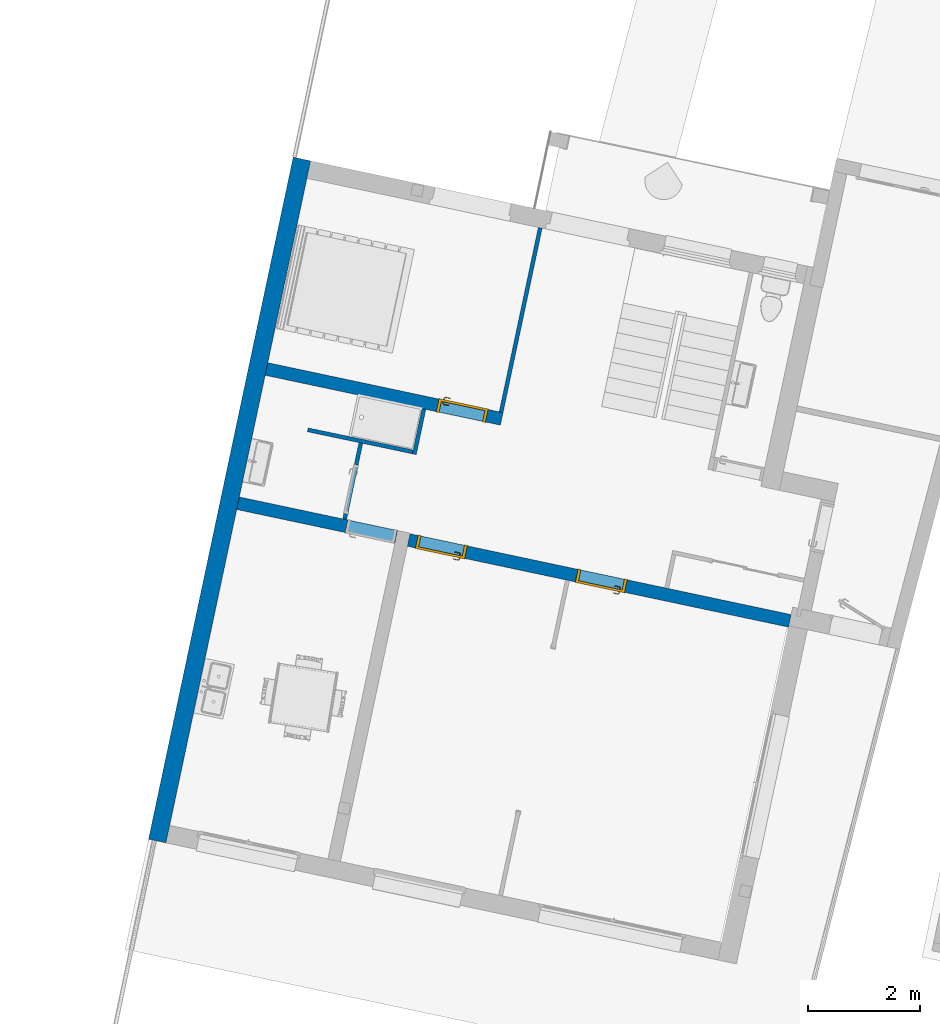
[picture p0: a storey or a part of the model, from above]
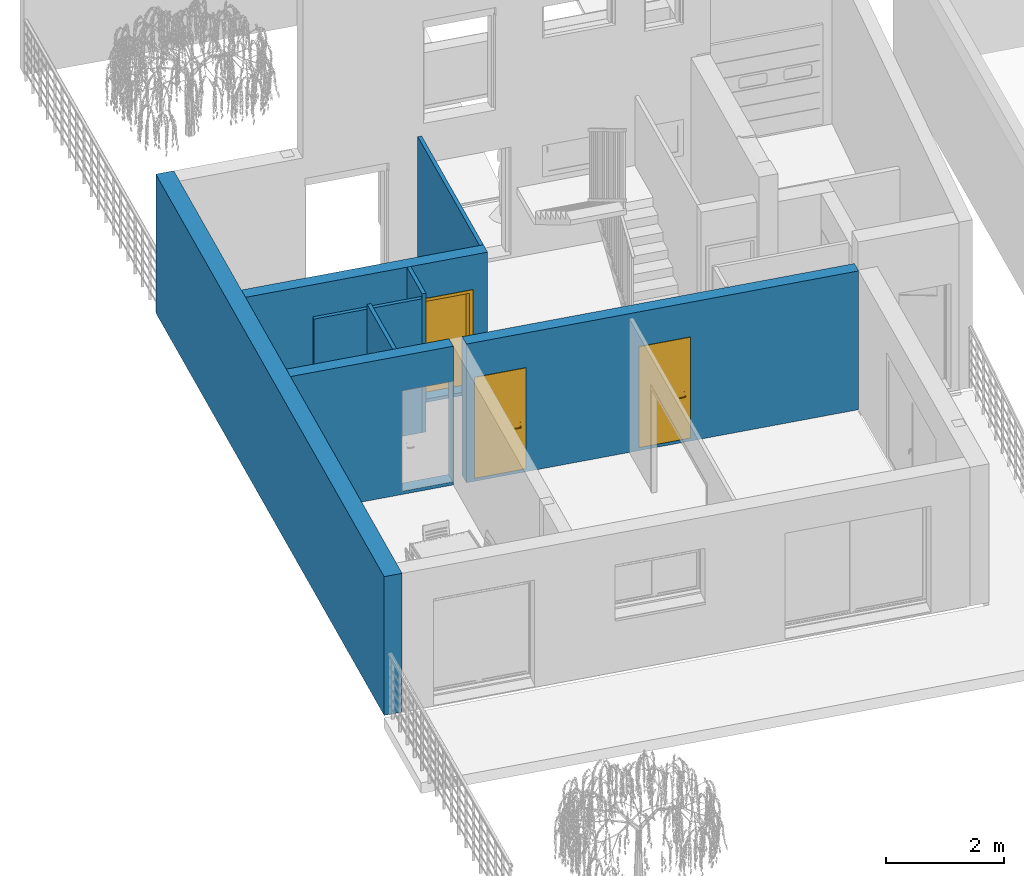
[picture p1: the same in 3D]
Properties of the parts of a building model (IFC2X3)

# File
Description: ViewDefinition [CoordinationView_V2.0]
Time: 2022-10-11T14:27:31
Written by: The EXPRESS Data Manager Version 5.02.0100.07 : 28 Aug 2013
Made in: 20190327_2315(x64) - Exporter 20.0.0.377 - Interface utilisateur alternative 20.0.0.377
Comment: STEP Physical File produced by: The EXPRESS Data Manager Version 5.02.0100.07 : 28 Aug 2013 * Module: EDMstepFileFactory/EDMstandAlone * Creation date: Tue Oct 11 14:27:31 2022 * Host: Khodri-Mohamed * Database: C:\Users\KHODRI~1\AppData\Local\Temp\b8559ccf-3b1b-4d22-95b2-55f6bca857a5\28f0a63c-8f12-43ca-b958-e8c956d41420\ifc * Database version: 5507 * Database creation date: Tue Oct 11 14:27:18 2022 * Schema: IFC2X3 * Model: DataRepository.ifc * Model creation date: Tue Oct 11 14:27:19 2022 * Header model: DataRepository.ifc_HeaderModel * Header model creation date: Tue Oct 11 14:27:19 2022 * EDMuser: sdai-user * EDMgroup: sdai-group * License ID and type: 5605 : Permanent license. Expiry date: * EDMstepFileFactory options: 020000

# IfcProject
LongName: CONSTRUCTION D'UNE HABITATION PRINCIPALE; Phase: PERMIS DE CONSTRUIRE

# IfcSite, Default
RefLatitude: 48, 52, 53, 759999; RefLongitude: 2, 25, 58, 79999; RefElevation: 0 m

# IfcSite: Portail PVC double - 01:Portail PVC double -3 m couleur noir ht 1,40 3, Portail PVC double - 01:Portail PVC double -3 m couleur noir ht 1,40 3:1927708
Material: Peinture - Noir, PVC - Gris fonçé

# IfcSite: Portail PVC simple - 01:Portail PVC simple -ht 1,40 m couleur gris, Portail PVC simple - 01:Portail PVC simple -ht 1,40 m couleur gris:1927764
Material: Peinture - Noir, PVC - Gris fonçé

# IfcBuilding
Pset_BuildingCommon - NumberOfStoreys: 4

# IfcBuildingStorey: Niveau:Ligne du Niveau (4)
Name | LongName | Elevation (m)
RDC | RDC | -0.0686872
Plan des fondations Maisons 1 et 2 | Plan des fondations Maisons 1 et 2 | 0
ETAGE | ETAGE | 2.8
Etage 1 | Etage 1 | 2.82

# IfcSpace (22)
InteriorOrExteriorSpace: INTERNAL
Name | In | LongName | Reference
626 | RDC | SALON 2 | SALON 2 626
627 | RDC | SALON 1 | SALON 1 627
628 | RDC | CUISINE | CUISINE 628
629 | RDC | SDB | SDB 629
630 | RDC | CH P | CH P 630
632 | RDC | GARAGE | GARAGE 632
633 | RDC | ENTREE | ENTREE 633
634 | RDC | PL | PL 634
637 | ETAGE | ch 4 | ch 4 637
638 | ETAGE | ch 2 | ch 2 638
639 | ETAGE | ch 1 | ch 1 639
641 | ETAGE | wc | wc 641
643 | RDC | WC | WC 643
644 | ETAGE | ch 3 | ch 3 644
645 | ETAGE | degt | degt 645
647 | ETAGE | sdb | sdb 647
648 | ETAGE | . | . 648
649 | ETAGE | . | . 649
656 | ETAGE | . | . 656
657 | ETAGE | . | . 657
658 | RDC | HALL | HALL 658
659 | RDC | Pièce | Pièce 659

# IfcBeam: 10 x 35 ht, Poutre rectangulaire - Béton:10 x 35 ht:1884701
In: Etage 1
Type - PredefinedType: BEAM
Type - Pset_BeamCommon - IsExternal: no; Reference: 10 x 35 ht
Type - Pset_QuantityTakeOff - Reference: 10 x 35 ht
Type - Pset_ReinforcementBarPitchOfBeam - Reference: 10 x 35 ht
Material: Béton - Béton coulé sur place; Group: Groupe de modèles:pergolas 2:1884699
Pset_BeamCommon - Span: 5.46 m; Slope: 0 deg
Pset_QuantityTakeOff - sets with these values: 2

# IfcBeam: 5 x 25 ht 2 (19)
In: Etage 1
Type - PredefinedType: BEAM
Type - Pset_BeamCommon - IsExternal: no; Reference: 5 x 25 ht 2
Type - Pset_QuantityTakeOff - Reference: 5 x 25 ht 2
Type - Pset_ReinforcementBarPitchOfBeam - Reference: 5 x 25 ht 2
Material: Béton - Béton coulé sur place; Group: Groupe de modèles:pergolas 2:1884699
Pset_BeamCommon - Slope: 0 deg
Pset_QuantityTakeOff - sets with these values: 2
Name (Poutre rectangulaire - Béton:5 x 25 ht 2:...) | Span (m)
1884707 | 1.66
1884709 | 1.66
1884711 | 1.646
1884713 | 1.631
1884715 | 1.616
1884717 | 1.601
1884719 | 1.587
1884721 | 1.572
1884723 | 1.557
1884725 | 1.542
1884727 | 1.528
1884729 | 1.513
1884731 | 1.498
1884733 | 1.484
1884737 | 1.468
1884739 | 1.453
1884741 | 1.438
1884743 | 1.424
1884745 | 1.409

# IfcBuildingElementProxy: LaRon, RPC Homme:LaRon:1914914
In: 657
Type - Pset_BuildingElementProxyCommon - Reference: LaRon
Type - Pset_QuantityTakeOff - Reference: LaRon
Pset_BuildingElementProxyCommon - sets with these values: 2

# IfcBuildingElementProxy: Lisa, RPC Femme:Lisa:1914892
In: 656
Type - Pset_BuildingElementProxyCommon - Reference: Lisa
Type - Pset_QuantityTakeOff - Reference: Lisa
Pset_BuildingElementProxyCommon - sets with these values: 2

# IfcBuildingElementProxy: Saule pleureur - 2.5 (4)
In: RDC
Type - Pset_BuildingElementProxyCommon - Reference: Saule pleureur - 2.5
Type - Pset_QuantityTakeOff - Reference: Saule pleureur - 2.5
Pset_BuildingElementProxyCommon - sets with these values: 2
Name (Arbre 3D - Saule pleureur:Saule pleureur - 2.5:...)
1939919
1939948
1939965
1939994

# IfcBuildingElementProxy: YinYin, RPC Femme:YinYin:1914956
In: RDC
Type - Pset_BuildingElementProxyCommon - Reference: YinYin
Type - Pset_QuantityTakeOff - Reference: YinYin
Pset_BuildingElementProxyCommon - sets with these values: 2

# IfcColumn: 20 X 20 (5)
Type - PredefinedType: COLUMN
Type - Pset_ColumnCommon - IsExternal: no; Reference: 20 X 20; LoadBearing: yes
Type - Pset_QuantityTakeOff - Reference: 20 X 20
Type - Pset_ReinforcementBarPitchOfColumn - Reference: 20 X 20
Pset_ColumnCommon - Slope: 0 deg
Pset_QuantityTakeOff - sets with these values: 2
Name (M_Béton-Carré-Poteau:20 X 20:...) | In | Material
1884703 | Plan des fondations Maisons 1 et 2 | Maçonnerie - Béton coulé sur place | Group: Groupe de modèles:pergolas 2:1884699
1884705 | Plan des fondations Maisons 1 et 2 | Maçonnerie - Béton coulé sur place | Group: Groupe de modèles:pergolas 2:1884699
1897064 | RDC | Béton - Béton coulé sur place
1897142 | RDC | Béton - Béton coulé sur place
1897328 | RDC | Béton - Béton coulé sur place

# IfcDoor: 140 - 90 x 210 cm - Gris, Avec panneau latéral:140 - 90 x 210 cm - Gris:1884574
In: Plan des fondations Maisons 1 et 2
Type - ParameterTakesPrecedence: no; Sizeable: no; Material: Peinture époxy - Gris, Verre
OverallHeight: 2.225 m; OverallWidth: 1.53 m
Pset_DoorCommon - IsExternal: yes; Reference: 140 - 90 x 210 cm - Gris
Pset_QuantityTakeOff - Reference: 140 - 90 x 210 cm - Gris

# IfcDoor: 83 x 204 - (80), FR_Simple (R):83 x 204 - (80):1891026
In: Plan des fondations Maisons 1 et 2
Type - OperationType: SINGLE_SWING_LEFT; ParameterTakesPrecedence: no; Sizeable: no; Material: Poignée Porte, Dormants Portes, Panneaux Portes
Type - FR_Simple (R):83 x 204 - (80):1891026 - PanelOperation: SWINGING
OverallHeight: 2.075 m; OverallWidth: 0.9 m
Pset_DoorCommon - IsExternal: no; Reference: 83 x 204 - (80)
Pset_QuantityTakeOff - Reference: 83 x 204 - (80)

# IfcDoor: 83 x 204 - (80), FR_Simple (R):83 x 204 - (80):1904554
In: Plan des fondations Maisons 1 et 2
Type - OperationType: SINGLE_SWING_LEFT; ParameterTakesPrecedence: no; Sizeable: no; Material: Poignée Porte, Dormants Portes, Panneaux Portes
Type - FR_Simple (R):83 x 204 - (80):1904554 - PanelOperation: SWINGING
OverallHeight: 2.075 m; OverallWidth: 0.9 m
Pset_DoorCommon - IsExternal: no; Reference: 83 x 204 - (80)
Pset_QuantityTakeOff - Reference: 83 x 204 - (80)

# IfcDoor: 83 x 204 - (80), FR_Simple (R):83 x 204 - (80):1884583
In: Plan des fondations Maisons 1 et 2
Type - OperationType: SINGLE_SWING_RIGHT; ParameterTakesPrecedence: no; Sizeable: no; Material: Poignée Porte, Dormants Portes, Panneaux Portes
Type - FR_Simple (R):83 x 204 - (80):1884583 - PanelOperation: SWINGING
OverallHeight: 2.075 m; OverallWidth: 0.9 m
Pset_DoorCommon - IsExternal: no; Reference: 83 x 204 - (80)
Pset_QuantityTakeOff - Reference: 83 x 204 - (80)

# IfcDoor: 83 x 204 - (80) (4)
In: Plan des fondations Maisons 1 et 2
Type - OperationType: SINGLE_SWING_RIGHT; ParameterTakesPrecedence: no; Sizeable: no; Material: Poignée Porte, Dormants Portes, Panneaux Portes
Type - FR_Simple (R):83 x 204 - (80):1884588 - PanelOperation: SWINGING
OverallHeight: 2.075 m; OverallWidth: 0.9 m
Pset_DoorCommon - IsExternal: no; Reference: 83 x 204 - (80)
Pset_QuantityTakeOff - Reference: 83 x 204 - (80)
Name (FR_Simple (R):83 x 204 - (80):...)
1884588
1884635
1884654
1891205

# IfcDoor: Garage sectionnelle 2.4 M x 2.00 ht, Garage sectionnelle:Garage sectionnelle 2.4 M x 2.00 ht:1884623
In: Plan des fondations Maisons 1 et 2
Type - ParameterTakesPrecedence: no; Sizeable: no; Material: Plastique - Noir, Peinture - Gris, Verre, Peinture - Grise
OverallHeight: 2.4 m; OverallWidth: 2.015 m
Pset_DoorCommon - IsExternal: no; Reference: Garage sectionnelle 2.4 M x 2.00 ht; ThermalTransmittance: 3.7021 kg/K/s3
Pset_QuantityTakeOff - Reference: Garage sectionnelle 2.4 M x 2.00 ht

# IfcDoor: Ouverture en rectangle 1.00 M, Ouverture en rectangle:Ouverture en rectangle 1.00 M:1884818
In: Plan des fondations Maisons 1 et 2
Type - ParameterTakesPrecedence: no; Sizeable: no; Material: RAL 212
OverallHeight: 2.35 m; OverallWidth: 1 m
Pset_DoorCommon - IsExternal: no; Reference: Ouverture en rectangle 1.00 M
Pset_QuantityTakeOff - Reference: Ouverture en rectangle 1.00 M

# IfcDoor: Ouverture en rectangle 3m, Ouverture en rectangle:Ouverture en rectangle 3m:1893428
In: RDC
Type - ParameterTakesPrecedence: no; Sizeable: no; Material: Bois - Chêne
OverallHeight: 2.15 m; OverallWidth: 3 m
Pset_DoorCommon - IsExternal: no; Reference: Ouverture en rectangle 3m
Pset_QuantityTakeOff - Reference: Ouverture en rectangle 3m

# IfcDoor: Ouverture en rectangle 4.50 M 3, Ouverture en rectangle:Ouverture en rectangle 4.50 M 3:1884817
In: RDC
Type - ParameterTakesPrecedence: no; Sizeable: no; Material: RAL 212
OverallHeight: 2.35 m; OverallWidth: 4.5 m
Pset_DoorCommon - IsExternal: no; Reference: Ouverture en rectangle 4.50 M 3
Pset_QuantityTakeOff - Reference: Ouverture en rectangle 4.50 M 3

# IfcDoor: PP (0.73m x 2.04m) (2)
In: ETAGE
Type - OperationType: SINGLE_SWING_LEFT; ParameterTakesPrecedence: no; Sizeable: no; Material: Finition Peinture - Blanc satiné, Bois - Mélaminé hêtre
Type - Int. Simple:PP (0.73m x 2.04m):1917461 - PanelOperation: SWINGING
OverallHeight: 2.075 m; OverallWidth: 0.8 m
Pset_DoorCommon - IsExternal: no; Reference: PP (0.73m x 2.04m); ThermalTransmittance: 3.7021 kg/K/s3
Pset_QuantityTakeOff - Reference: PP (0.73m x 2.04m)
Name (Int. Simple:PP (0.73m x 2.04m):...)
1917461
1930670

# IfcDoor: PP (0.73m x 2.04m) (2)
In: ETAGE
Type - OperationType: SINGLE_SWING_RIGHT; ParameterTakesPrecedence: no; Sizeable: no; Material: Finition Peinture - Blanc satiné, Bois - Mélaminé hêtre
Type - Int. Simple:PP (0.73m x 2.04m):1899424 - PanelOperation: SWINGING
OverallHeight: 2.075 m; OverallWidth: 0.8 m
Pset_DoorCommon - IsExternal: no; Reference: PP (0.73m x 2.04m); ThermalTransmittance: 3.7021 kg/K/s3
Pset_QuantityTakeOff - Reference: PP (0.73m x 2.04m)
Name (Int. Simple:PP (0.73m x 2.04m):...)
1899424
1930071

# IfcDoor: PP (0.73m x 2.04m) (2)
In: ETAGE
Type - OperationType: SINGLE_SWING_RIGHT; ParameterTakesPrecedence: no; Sizeable: no; Material: Finition Peinture - Blanc satiné, Bois - Mélaminé hêtre
Type - Int. Simple:PP (0.73m x 2.04m):1901654 - PanelOperation: SWINGING
OverallHeight: 2.075 m; OverallWidth: 0.8 m
Pset_DoorCommon - IsExternal: no; Reference: PP (0.73m x 2.04m); ThermalTransmittance: 3.7021 kg/K/s3
Pset_QuantityTakeOff - Reference: PP (0.73m x 2.04m)
Name (Int. Simple:PP (0.73m x 2.04m):...)
1901654
1912241

# IfcDoor: PP Oculus haut (0.90m x 2.15m), Ext. Simple:PP Oculus haut (0.90m x 2.15m):1884629
In: Plan des fondations Maisons 1 et 2
Type - OperationType: SINGLE_SWING_RIGHT; ParameterTakesPrecedence: no; Sizeable: no; Material: PVC - Blanc, Verre
Type - Ext. Simple:PP Oculus haut (0.90m x 2.15m):1884629 - PanelOperation: SWINGING
OverallHeight: 2.2 m; OverallWidth: 1 m
Pset_DoorCommon - IsExternal: yes; Reference: PP Oculus haut (0.90m x 2.15m)
Pset_QuantityTakeOff - Reference: PP Oculus haut (0.90m x 2.15m)

# IfcDoor: Placard coulissante - 2 panneaux, Placard coulissante - 2 panneaux:Placard coulissante - 2 panneaux:1894947
In: RDC
Type - ParameterTakesPrecedence: no; Sizeable: no; Material: Placard - Profil, Placard - Encadrement, Placard - Porte
OverallHeight: 2.1 m; OverallWidth: 1.2 m
Pset_DoorCommon - IsExternal: no; Reference: Placard coulissante - 2 panneaux
Pset_QuantityTakeOff - Reference: Placard coulissante - 2 panneaux

# IfcFlowTerminal: Baignoire rectangulaire - Mur:Baignoire rectangulaire - Mur 70 x 170, Baignoire rectangulaire - Mur:Baignoire rectangulaire - Mur 70 x 170:1929937
In: 647
Material: Céramique - Blanche
Pset_DistributionFlowElementCommon - Reference: Baignoire rectangulaire - Mur 70 x 170; sets with these values: 2

# IfcFlowTerminal: FR_Bac à douches - Vidange Axée:80 X 140, FR_Bac à douches - Vidange Axée:80 X 140:1912669
In: 645
Classification: D2010710 Showers (Uniformat); Material: Blanc - Element de salle de bains
Pset_DistributionFlowElementCommon - Reference: 80 X 140; sets with these values: 2

# IfcFlowTerminal: FR_Bac à douches - Vidange Axée:80 x 120 (5)
Classification: D2010710 Showers (Uniformat); Material: Blanc - Element de salle de bains
Pset_DistributionFlowElementCommon - Reference: 80 x 120; sets with these values: 2
Name (FR_Bac à douches - Vidange Axée:80 x 120:...) | In
1884580 | 629
1912712 | 645
1912743 | 645
1912770 | 649
1912811 | 639

# IfcFlowTerminal: Lavabo sur console métallique:100 x 47 x 85 cm - Blanc, Lavabo sur console métallique:100 x 47 x 85 cm - Blanc:1912585
In: 647
Material: Métal - Chrome, Céramique - Blanc
Pset_DistributionFlowElementCommon - Reference: 100 x 47 x 85 cm - Blanc; sets with these values: 2

# IfcFlowTerminal: Lavabo sur console métallique:80 x 40 x 85 cm - Blanc 3 (2)
Material: Métal - Chrome, Céramique - Blanc
Pset_DistributionFlowElementCommon - Reference: 80 x 40 x 85 cm - Blanc 3; sets with these values: 2
Name (Lavabo sur console métallique:80 x 40 x 85 cm - Blanc 3:...) | In
1884581 | 629
1884582 | 643

# IfcFlowTerminal: M_Cuvette réservoir-3D:M_Cuvette réservoir-3D (2)
Material: Porcelaine - Lin, Stratifié - Lin,Mat
Pset_DistributionFlowElementCommon - Reference: M_Cuvette réservoir-3D; sets with these values: 2
Name (M_Cuvette réservoir-3D:M_Cuvette réservoir-3D:...) | In
1884586 | 643
1912626 | 641

# IfcFlowTerminal: M_Evier-Double:1000 x 535 mm, M_Evier-Double:1000 x 535 mm:1884590
In: 628
Material: Métal - Acier, Poli
Pset_DistributionFlowElementCommon - Reference: 1000 x 535 mm; sets with these values: 2

# IfcFurnishingElement: 1,40 mm x 2000 mm 2 (4)
Type - Material: Textile - Bleu pâle, Bois - Teck, Plastique - Noir
Pset_QuantityTakeOff - Reference: 1,40 mm x 2000 mm 2
Name (Lit à lattes:1,40 mm x 2000 mm 2:...) | In
1914643 | 639
1914668 | 638
1914691 | 637
1914716 | 644

# IfcFurnishingElement: 1100 mm x 1100 mm x 760 mm, MS-Table et chaises:1100 mm x 1100 mm x 760 mm:1884593
In: 628
Type - Material: Bois - Exotique
Pset_QuantityTakeOff - Reference: 1100 mm x 1100 mm x 760 mm

# IfcFurnishingElement: 1900 mm x 2000 mm, Lit à lattes:1900 mm x 2000 mm:1884587
In: 630
Type - Material: Textile - Bleu pâle, Bois - Teck, Plastique - Noir
Pset_QuantityTakeOff - Reference: 1900 mm x 2000 mm

# IfcOpeningElement: Opening (43)
Name | In
3 x Mur de base:Ext. Parpaing 20 + Isolant 12 enduit blanc cassé 2:1884566 | RDC | Pset_QuantityTakeOff - Reference: Ext. Parpaing 20 + Isolant 12 enduit blanc cassé 2; sets with these values: 2
2 x Mur de base:Ext. Parpaing 2 + 20 + 2:1884571 | RDC | Pset_QuantityTakeOff - Reference: Ext. Parpaing 2 + 20 + 2; sets with these values: 2
Mur de base:Int. Platre 70 mm en blanc:1884575 | RDC | Pset_QuantityTakeOff - Reference: Int. Platre 70 mm en blanc; sets with these values: 2
Int. Simple:PP (0.73m x 2.04m):1930670:1 | ETAGE
Sol:Dalle Béton terrasse - 10 cm 2:1884595:2 | ETAGE | Pset_OpeningElementCommon - Reference: Dalle Béton terrasse - 10 cm 2; sets with these values: 2
Mur de base:Ext. Parpaing 2 + 20 + 2:1884815 | RDC | Pset_QuantityTakeOff - Reference: Ext. Parpaing 2 + 20 + 2; sets with these values: 2
Int. Simple:PP (0.73m x 2.04m):1930071:1 | ETAGE
Mur de base:Int. Platre 70 mm en blanc:1906597 | ETAGE | Pset_QuantityTakeOff - Reference: Int. Platre 70 mm en blanc; sets with these values: 2
4 x Mur de base:Ext. Parpaing 20 + 2 x 1.5:1908481 | ETAGE | Pset_QuantityTakeOff - Reference: Ext. Parpaing 20 + 2 x 1.5; sets with these values: 2
Mur de base:EXT PIERRE DE PREMENT:1848028 | RDC | Pset_QuantityTakeOff - Reference: EXT PIERRE DE PREMENT; sets with these values: 2
Mur de base:EXT PIERRE DE PREMENT:1911835:1 | RDC | Pset_QuantityTakeOff - Reference: EXT PIERRE DE PREMENT; sets with these values: 2
Int. Simple:PP (0.73m x 2.04m):1912241:1 | ETAGE
Mur de base:Ext. Parpaing 20 + Isolant 10 enduit blanc cassé:1923041 | ETAGE | Pset_QuantityTakeOff - Reference: Ext. Parpaing 20 + Isolant 10 enduit blanc cassé; sets with these values: 2
Int. Simple:PP (0.73m x 2.04m):1917461:1 | ETAGE
3 x Mur de base:Ext. Parpaing 20 + Isolant 10 enduit blanc cassé:1884570 | RDC
Mur de base:Ext. Parpaing 2 + 20 + 2:1884572 | RDC
FR_Simple (R):83 x 204 - (80):1884588:1 | RDC
FR_Simple (R):83 x 204 - (80):1884583:1 | RDC
FR_Simple (R):83 x 204 - (80):1884635:1 | RDC
Mur de base:Ext. Parpaing 20 + Isolant 12 enduit blanc cassé 2:1884628 | RDC
FR_Simple (R):83 x 204 - (80):1884654:1 | RDC
FR_Simple (R):83 x 204 - (80):1891205:1 | RDC
Ouverture en rectangle:Ouverture en rectangle 3m:1893428:1 | RDC
Mur de base:Ext. Parpaing 20 + Isolant 10 enduit blanc cassé:1884671 | ETAGE
2 x Mur de base:Ext. Parpaing 20 + Isolant 10 enduit blanc cassé:1884672 | ETAGE
Int. Simple:PP (0.73m x 2.04m):1901654:1 | ETAGE
Ouverture en rectangle:Ouverture en rectangle 4.50 M 3:1884817:1 | RDC
Ouverture en rectangle:Ouverture en rectangle 1.00 M:1884818:1 | Plan des fondations Maisons 1 et 2
FR_Simple (R):83 x 204 - (80):1891026:1 | RDC
Placard coulissante - 2 panneaux:Placard coulissante - 2 panneaux:1894947:1 | RDC
Mur de base:Ext. Parpaing 20 + Isolant 12 enduit blanc cassé 2:1892923 | RDC
Mur de base:Ext. Parpaing 20 + Isolant 10 enduit blanc cassé:1898685 | ETAGE
Int. Simple:PP (0.73m x 2.04m):1899424:1 | ETAGE
FR_Simple (R):83 x 204 - (80):1904554:1 | RDC

# IfcRailing: Garde-corps:CLOTURE 1, Garde-corps:CLOTURE 1:1894222
In: RDC
Material: Peinture - Grise, Peinture - BLEU
Pset_QuantityTakeOff - Reference: CLOTURE 1
Pset_RailingCommon - IsExternal: no; Reference: CLOTURE 1; Height: 1.2 m

# IfcRailing: Garde-corps:Type Bateau 1,25 m (6)
Material: noir acier, Finition Peinture Grise
Pset_QuantityTakeOff - Reference: Type Bateau 1,25 m
Pset_RailingCommon - IsExternal: no; Reference: Type Bateau 1,25 m; Height: 1.2192 m
Name (Garde-corps:Type Bateau 1,25 m:...) | In
1913379 | ETAGE
1913560 | ETAGE
1916439 | ETAGE
1927442 | RDC
1927614 | RDC
1927668 | RDC

# IfcRoof: Toit de base:Toit - 100 rouge, Toit de base:Toit - 100 rouge:1940180
In: RDC
Pset_QuantityTakeOff - Reference: Toit - 100 rouge
Pset_RoofCommon - IsExternal: yes; Reference: Toit - 100 rouge; ProjectedArea: 70.6925 m2; TotalArea: 81.6287 m2
Group: Groupe de modèles:GRANGE EXISTANTE:1940285

# IfcSlab: Palier monobloc:Epaisseur 150 mm, Escalier coulé sur place:Escalier:1893858 Landing 1
In: RDC
PredefinedType: LANDING
Pset_QuantityTakeOff - Reference: Epaisseur 150 mm; sets with these values: 2
Pset_SlabCommon - IsExternal: no; PitchAngle: 0 deg; Reference: Epaisseur 150 mm

# IfcSlab: Sol:Dalle Béton + gravillon + isolant (3)
In: Etage 1
Type - PredefinedType: FLOOR; Material: gravillon 0.05 m, Isolant 0.1 m, Béton 0.2 m
Type - Pset_QuantityTakeOff - Reference: Dalle Béton + gravillon + isolant
Type - Pset_ReinforcementBarPitchOfSlab - Reference: Dalle Béton + gravillon + isolant
Type - Pset_SlabCommon - IsExternal: no; Reference: Dalle Béton + gravillon + isolant
Pset_QuantityTakeOff - sets with these values: 2
Pset_SlabCommon - LoadBearing: no; PitchAngle: 0 deg
Name (Sol:Dalle Béton + gravillon + isolant:...)
1884763
1884828
1924773

# IfcSlab: Sol:Dalle Béton butume commun 10 cm 2, Sol:Dalle Béton butume commun 10 cm 2:1884605
In: RDC
Type - PredefinedType: FLOOR; Material: Peinture - Or 0.1 m
Type - Pset_QuantityTakeOff - Reference: Dalle Béton butume commun 10 cm 2
Type - Pset_ReinforcementBarPitchOfSlab - Reference: Dalle Béton butume commun 10 cm 2
Type - Pset_SlabCommon - IsExternal: no; Reference: Dalle Béton butume commun 10 cm 2
Pset_QuantityTakeOff - sets with these values: 2
Pset_SlabCommon - LoadBearing: no; PitchAngle: 0 deg

# IfcSlab: Sol:Dalle Béton rue - 10 cm, Sol:Dalle Béton rue - 10 cm:1939522
In: RDC
Type - PredefinedType: FLOOR; Material: Béton rue 0.1 m
Type - Pset_QuantityTakeOff - Reference: Dalle Béton rue - 10 cm
Type - Pset_ReinforcementBarPitchOfSlab - Reference: Dalle Béton rue - 10 cm
Type - Pset_SlabCommon - IsExternal: no; Reference: Dalle Béton rue - 10 cm
Pset_QuantityTakeOff - sets with these values: 2
Pset_SlabCommon - LoadBearing: no; PitchAngle: 0 deg

# IfcSlab: Sol:Dalle Béton terrasse - 10 cm 2 (2)
Type - PredefinedType: FLOOR; Material: Béton 0.1 m
Type - Pset_QuantityTakeOff - Reference: Dalle Béton terrasse - 10 cm 2
Type - Pset_ReinforcementBarPitchOfSlab - Reference: Dalle Béton terrasse - 10 cm 2
Type - Pset_SlabCommon - IsExternal: no; Reference: Dalle Béton terrasse - 10 cm 2
Pset_QuantityTakeOff - sets with these values: 2
Pset_SlabCommon - LoadBearing: no; PitchAngle: 0 deg
Name (Sol:Dalle Béton terrasse - 10 cm 2:...) | In
1884595 | ETAGE
1924798 | Etage 1

# IfcSlab: Sol:terrasse EXT CARRELE (3)
In: RDC
Type - PredefinedType: FLOOR; Material: TERRASSE EXT 0.02 m, planchers interieurs 0.2 m
Type - Pset_QuantityTakeOff - Reference: terrasse EXT CARRELE
Type - Pset_ReinforcementBarPitchOfSlab - Reference: terrasse EXT CARRELE
Type - Pset_SlabCommon - IsExternal: no; Reference: terrasse EXT CARRELE
Pset_QuantityTakeOff - sets with these values: 2
Pset_SlabCommon - LoadBearing: no; PitchAngle: 0 deg
Name (Sol:terrasse EXT CARRELE:...)
1884615
1936709
1939158

# IfcSlab: Toit de base:Toit - 100 rouge (2)
In: RDC
PredefinedType: ROOF; Material: Appui 0.05 m; Group: Groupe de modèles:GRANGE EXISTANTE:1940285
Pset_QuantityTakeOff - Reference: Toit - 100 rouge; sets with these values: 2
Pset_SlabCommon - IsExternal: yes; Reference: Toit - 100 rouge; PitchAngle: 30 deg

# IfcStair: Escalier coulé sur place:Monobloc, Escalier coulé sur place:Escalier:1893858
In: RDC
Pset_QuantityTakeOff - Reference: Monobloc
Pset_StairCommon - Reference: Monobloc; IsExternal: no; NumberOfRiser: 16; NumberOfTreads: 14; RiserHeight: 0.179293 m; TreadLength: 0.271414 m

# IfcStair: Escalier:Monobloc (22)
In: Plan des fondations Maisons 1 et 2
Pset_QuantityTakeOff - Reference: Monobloc
Pset_StairCommon - Reference: Monobloc; IsExternal: no
Name (Escalier:Monobloc:...) | NumberOfRiser = NumberOfTreads | RiserHeight (m) | TreadLength (m)
78219 | 15 | 0.173333 | 0.283333
78348 | 15 | 0.173333 | 0.283333
277315 | 17 | 0.158824 | 0.312353
277472 | 17 | 0.158824 | 0.312353
277700 | 17 | 0.158824 | 0.312353
277873 | 17 | 0.158824 | 0.312353
342772 | 15 | 0.18 | 0.27
342952 | 15 | 0.18 | 0.27
343084 | 15 | 0.18 | 0.27
343204 | 15 | 0.18 | 0.27
352512 | 15 | 0.18 | 0.27
353029 | 15 | 0.18 | 0.27
368055 | 15 | 0.18 | 0.27
368180 | 15 | 0.18 | 0.27
368300 | 14 | 0.18 | 0.27
369629 | 15 | 0.18 | 0.27
373361 | 15 | 0.18 | 0.27
373488 | 15 | 0.18 | 0.27
376794 | 15 | 0.18 | 0.27
384406 | 15 | 0.18 | 0.27
384573 | 14 | 0.18 | 0.27
384807 | 15 | 0.18 | 0.27

# IfcStair: Escalier:Monobloc 2, Escalier:Monobloc 2:515021
In: Plan des fondations Maisons 1 et 2
Pset_QuantityTakeOff - Reference: Monobloc 2
Pset_StairCommon - IsExternal: no; Reference: Monobloc 2; NumberOfRiser: 15; NumberOfTreads: 15; RiserHeight: 0.18 m; TreadLength: 0.3 m

# IfcStairFlight: Volée monobloc:Nez de marche 5 mm (2)
In: RDC
NumberOfRiser: 8; NumberOfTreads: 7; RiserHeight: 0.588231 m; TreadLength: 0.890466 m
Pset_QuantityTakeOff - Reference: Nez de marche 5 mm
Pset_StairFlightCommon - Reference: Nez de marche 5 mm; NumberOfRiser: 16; NumberOfTreads: 14; RiserHeight: 0.179293 m; TreadLength: 0.271414 m; NosingLength: 0.005 m; WalkingLineOffset: 0.5 m; TreadLengthAtOffset: 0.271414 m; WaistThickness: 1 m
Name (Escalier coulé sur place:Escalier:...)
1893858 Run 1
1893858 Run 2

# IfcWall: Mur de base:Ext. Parpaing 20 + Isolant 10 enduit blanc CASSE, Mur de base:Ext. Parpaing 20 + Isolant 10 enduit blanc CASSE:1884695
In: RDC
Type - PredefinedType: STANDARD; Material: Enduit blanc cassé2 0.02 m, Parpaing 0.2 m, Isolant 0.1 m
Type - Pset_QuantityTakeOff - Reference: Ext. Parpaing 20 + Isolant 10 enduit blanc CASSE
Type - Pset_ReinforcementBarPitchOfWall - Reference: Ext. Parpaing 20 + Isolant 10 enduit blanc CASSE
Type - Pset_WallCommon - IsExternal: no; Reference: Ext. Parpaing 20 + Isolant 10 enduit blanc CASSE
Material: Enduit blanc cassé2, Parpaing, Isolant
Pset_QuantityTakeOff - sets with these values: 2
Pset_WallCommon - IsExternal: yes; ExtendToStructure: no; LoadBearing: no

# IfcWall: Mur de base:Ext. Parpaing 20 + Isolant 10 enduit blanc cassé, Mur de base:Ext. Parpaing 20 + Isolant 10 enduit blanc cassé:1904710
In: ETAGE
Type - PredefinedType: STANDARD; Material: Enduit blanc cassé2 0.02 m, Parpaing 0.2 m, Isolant 0.1 m
Type - Pset_QuantityTakeOff - Reference: Ext. Parpaing 20 + Isolant 10 enduit blanc cassé
Type - Pset_ReinforcementBarPitchOfWall - Reference: Ext. Parpaing 20 + Isolant 10 enduit blanc cassé
Type - Pset_WallCommon - IsExternal: no; Reference: Ext. Parpaing 20 + Isolant 10 enduit blanc cassé
Pset_QuantityTakeOff - sets with these values: 2
Pset_WallCommon - IsExternal: yes; ExtendToStructure: no; LoadBearing: no

# IfcWallStandardCase: Mur de base:EXT PIERRE DE PREMENT (2)
In: RDC
Type - PredefinedType: STANDARD; Material: PIERRE DE PAREMENT 0.01 m
Type - Pset_QuantityTakeOff - Reference: EXT PIERRE DE PREMENT
Type - Pset_ReinforcementBarPitchOfWall - Reference: EXT PIERRE DE PREMENT
Type - Pset_WallCommon - IsExternal: no; Reference: EXT PIERRE DE PREMENT
Pset_QuantityTakeOff - sets with these values: 2
Pset_WallCommon - ExtendToStructure: no; LoadBearing: no
Name (Mur de base:EXT PIERRE DE PREMENT:...)
1911059
1911835

# IfcWallStandardCase: Mur de base:Ext. Parpaing 2 + 20 + 2 (6)
Type - PredefinedType: STANDARD; Material: Enduit blanc cassé2 0.02 m, Parpaing 0.2 m, Enduit blanc cassé2 0.02 m
Type - Pset_QuantityTakeOff - Reference: Ext. Parpaing 2 + 20 + 2
Type - Pset_ReinforcementBarPitchOfWall - Reference: Ext. Parpaing 2 + 20 + 2
Type - Pset_WallCommon - IsExternal: no; Reference: Ext. Parpaing 2 + 20 + 2
Pset_QuantityTakeOff - sets with these values: 2
Pset_WallCommon - IsExternal: yes; ExtendToStructure: no; LoadBearing: no
Name (Mur de base:Ext. Parpaing 2 + 20 + 2:...) | In
1884571 | RDC
1884572 | RDC
1884815 | RDC
1884816 | Plan des fondations Maisons 1 et 2
1884822 | RDC
1919690 | RDC

# IfcWallStandardCase: Mur de base:Ext. Parpaing 20 + 2 x 1.5 (13)
Type - PredefinedType: STANDARD; Material: Enduit blanc cassé2 0.015 m, Parpaing 0.2 m, Enduit blanc cassé2 0.015 m
Type - Pset_QuantityTakeOff - Reference: Ext. Parpaing 20 + 2 x 1.5
Type - Pset_ReinforcementBarPitchOfWall - Reference: Ext. Parpaing 20 + 2 x 1.5
Type - Pset_WallCommon - IsExternal: no; Reference: Ext. Parpaing 20 + 2 x 1.5
Pset_QuantityTakeOff - sets with these values: 2
Pset_WallCommon - IsExternal: yes; ExtendToStructure: no; LoadBearing: no
Name (Mur de base:Ext. Parpaing 20 + 2 x 1.5:...) | In
1884576 | RDC
1884585 | RDC
1884611 | RDC
1884639 | RDC
1884773 | ETAGE
1891025 | RDC
1908130 | ETAGE
1908473 | ETAGE
1908481 | ETAGE
1913555 | ETAGE
1927815 | RDC
1927843 | RDC
1928100 | RDC

# IfcWallStandardCase: Mur de base:Ext. Parpaing 20 + Isolant 10 enduit blanc cassé (8)
Type - PredefinedType: STANDARD; Material: Enduit blanc cassé2 0.02 m, Parpaing 0.2 m, Isolant 0.1 m
Type - Pset_QuantityTakeOff - Reference: Ext. Parpaing 20 + Isolant 10 enduit blanc cassé
Type - Pset_ReinforcementBarPitchOfWall - Reference: Ext. Parpaing 20 + Isolant 10 enduit blanc cassé
Type - Pset_WallCommon - IsExternal: no; Reference: Ext. Parpaing 20 + Isolant 10 enduit blanc cassé
Pset_QuantityTakeOff - sets with these values: 2
Pset_WallCommon - IsExternal: yes; ExtendToStructure: no; LoadBearing: no
Name (Mur de base:Ext. Parpaing 20 + Isolant 10 enduit blanc cassé:...) | In
1884568 | RDC
1884570 | RDC
1884671 | ETAGE
1884672 | ETAGE
1890400 | ETAGE
1898685 | ETAGE
1904965 | ETAGE
1923041 | ETAGE

# IfcWallStandardCase: Mur de base:Ext. Parpaing 20 + Isolant 12 enduit blanc cassé 2 (4)
In: RDC
Type - PredefinedType: STANDARD; Material: Enduit blanc cassé2 0.02 m, Parpaing 0.2 m, Isolant 0.12 m
Type - Pset_QuantityTakeOff - Reference: Ext. Parpaing 20 + Isolant 12 enduit blanc cassé 2
Type - Pset_ReinforcementBarPitchOfWall - Reference: Ext. Parpaing 20 + Isolant 12 enduit blanc cassé 2
Type - Pset_WallCommon - IsExternal: no; Reference: Ext. Parpaing 20 + Isolant 12 enduit blanc cassé 2
Pset_QuantityTakeOff - sets with these values: 2
Pset_WallCommon - IsExternal: yes; ExtendToStructure: no; LoadBearing: no
Name (Mur de base:Ext. Parpaing 20 + Isolant 12 enduit blanc cassé 2:...)
1884566
1884628
1892923
1919712

# IfcWallStandardCase: Mur de base:Générique - Ext. 150 mm (4)
In: RDC
Type - PredefinedType: STANDARD; Material: Mur par défaut 0.15 m
Type - Pset_QuantityTakeOff - Reference: Générique - Ext. 150 mm
Type - Pset_ReinforcementBarPitchOfWall - Reference: Générique - Ext. 150 mm
Type - Pset_WallCommon - IsExternal: no; Reference: Générique - Ext. 150 mm
Pset_QuantityTakeOff - sets with these values: 2
Pset_WallCommon - IsExternal: yes; LoadBearing: no
Group: Groupe de modèles:GRANGE EXISTANTE:1940285
Name (Mur de base:Générique - Ext. 150 mm:...) | ExtendToStructure
1940064 | yes
1940097 | yes
1940122 | yes
1940148 | no

# IfcWallStandardCase: Mur de base:Int. Platre 100 mm en blanc 2 (5)
Type - PredefinedType: STANDARD; Material: Blanc - Element de salle de bains 0.1 m
Type - Pset_QuantityTakeOff - Reference: Int. Platre 100 mm en blanc 2
Type - Pset_ReinforcementBarPitchOfWall - Reference: Int. Platre 100 mm en blanc 2
Type - Pset_WallCommon - IsExternal: no; Reference: Int. Platre 100 mm en blanc 2
Pset_QuantityTakeOff - sets with these values: 2
Pset_WallCommon - ExtendToStructure: no; LoadBearing: no
Name (Mur de base:Int. Platre 100 mm en blanc 2:...) | In
1884677 | ETAGE
1899819 | ETAGE
1928604 | RDC
1930212 | ETAGE
1930223 | ETAGE

# IfcWallStandardCase: Mur de base:Int. Platre 70 mm (6)
In: ETAGE
Type - PredefinedType: STANDARD; Material: Mur par défaut 0.07 m
Type - Pset_QuantityTakeOff - Reference: Int. Platre 70 mm
Type - Pset_ReinforcementBarPitchOfWall - Reference: Int. Platre 70 mm
Type - Pset_WallCommon - IsExternal: no; Reference: Int. Platre 70 mm
Pset_QuantityTakeOff - sets with these values: 2
Pset_WallCommon - ExtendToStructure: no; LoadBearing: no
Name (Mur de base:Int. Platre 70 mm:...)
1884680
1906307
1917462
1922836
1930070
1930315

# IfcWallStandardCase: Mur de base:Int. Platre 70 mm en blanc (12)
Type - PredefinedType: STANDARD; Material: Blanc - Element de salle de bains 0.07 m
Type - Pset_QuantityTakeOff - Reference: Int. Platre 70 mm en blanc
Type - Pset_ReinforcementBarPitchOfWall - Reference: Int. Platre 70 mm en blanc
Type - Pset_WallCommon - IsExternal: no; Reference: Int. Platre 70 mm en blanc
Pset_QuantityTakeOff - sets with these values: 2
Pset_WallCommon - ExtendToStructure: no; LoadBearing: no
Name (Mur de base:Int. Platre 70 mm en blanc:...) | In
1884575 | RDC
1884584 | RDC
1884640 | RDC
1884681 | ETAGE
1891599 | RDC
1891616 | RDC
1904414 | RDC
1906597 | ETAGE
1918925 | RDC
1919038 | RDC
1922840 | ETAGE
1923385 | ETAGE

# IfcWindow: .60 X 0.85 HT 2 (2)
Type - OperationType: SINGLE_PANEL; ParameterTakesPrecedence: no; Sizeable: no; Material: Fenêtre - Poignée, Fenêtre - Appui, Verre - Opaque Blanc, PVC - Blanc, Fenêtre - Cadre
OverallHeight: 1.08 m; OverallWidth: 0.7 m
Pset_QuantityTakeOff - Reference: .60 X 0.85 HT 2
Pset_WindowCommon - IsExternal: yes; Reference: .60 X 0.85 HT 2
Name (1 Vantail - Droit:.60 X 0.85 HT 2:...) | In
1906546 | ETAGE
1908815 | Etage 1

# IfcWindow: 0.60 X 0.70, 1 Vantail - Droit:0.60 X 0.70:1898019
In: RDC
Type - OperationType: SINGLE_PANEL; ParameterTakesPrecedence: no; Sizeable: no; Material: Fenêtre - Poignée, Fenêtre - Appui, Verre - Opaque Blanc, PVC - Blanc, Fenêtre - Cadre
OverallHeight: 1.08 m; OverallWidth: 0.7 m
Pset_QuantityTakeOff - Reference: 0.60 X 0.70
Pset_WindowCommon - IsExternal: yes; Reference: 0.60 X 0.70

# IfcWindow: 0.80 x 1.60 HT, 1 Vantail - Imposte basse:0.80 x 1.60 HT:1884694
In: Etage 1
Type - OperationType: DOUBLE_PANEL_HORIZONTAL; ParameterTakesPrecedence: no; Sizeable: no; Material: Fenêtre - Poignée, Fenêtre - Appui, Fenêtre - Vitrage, PVC - Gris foncé
OverallHeight: 1.73 m; OverallWidth: 0.9 m
Pset_QuantityTakeOff - Reference: 0.80 x 1.60 HT
Pset_WindowCommon - IsExternal: yes; Reference: 0.80 x 1.60 HT; ThermalTransmittance: 5.5617 kg/K/s3

# IfcWindow: 1.20 X 0.60 HT Appui Béton 3 (2)
Type - OperationType: SINGLE_PANEL; ParameterTakesPrecedence: no; Sizeable: no; Material: Fenêtre - Poignée, Fenêtre - Appui, PVC - Blanc, Fenêtre - Cadre, Fenêtre - Vitrage
OverallHeight: 1.08 m; OverallWidth: 1.3 m
Pset_QuantityTakeOff - Reference: 1.20 X 0.60 HT Appui Béton 3
Pset_WindowCommon - IsExternal: yes; Reference: 1.20 X 0.60 HT Appui Béton 3
Name (1 Vantail - Droit:1.20 X 0.60 HT Appui Béton 3:...) | In
1898225 | RDC
1906932 | ETAGE

# IfcWindow: 1.60 X 1.05 HT, VR-2 Vantaux:1.60 X 1.05 HT:1884664
In: Plan des fondations Maisons 1 et 2
Type - ParameterTakesPrecedence: no; Sizeable: no; Material: PVC - Blanc, Aluminium - Satiné, Béton - Ordinaire, Verre - Opaque Blanc
OverallHeight: 1.35 m; OverallWidth: 1.7 m
Pset_QuantityTakeOff - Reference: 1.60 X 1.05 HT
Pset_WindowCommon - IsExternal: yes; Reference: 1.60 X 1.05 HT

# IfcWindow: 120 x 135 cm, VR-2 Vantaux:120 x 135 cm:1907414
In: ETAGE
Type - ParameterTakesPrecedence: no; Sizeable: no; Material: PVC - Blanc, Aluminium - Satiné, Béton - Ordinaire, Verre - Opaque Blanc
OverallHeight: 1.65 m; OverallWidth: 1.3 m
Pset_QuantityTakeOff - Reference: 120 x 135 cm
Pset_WindowCommon - IsExternal: yes; Reference: 120 x 135 cm

# IfcWindow: 120 x 190 cm 3 (3)
In: ETAGE
Type - ParameterTakesPrecedence: no; Sizeable: no; Material: PVC - Blanc, Aluminium - Satiné, Béton - Ordinaire, Verre - Opaque Blanc
OverallHeight: 2.15456 m; OverallWidth: 1.3 m
Pset_QuantityTakeOff - Reference: 120 x 190 cm 3
Pset_WindowCommon - IsExternal: yes; Reference: 120 x 190 cm 3
Name (PF-VR-2 Vantaux:120 x 190 cm 3:...)
1884690
1907360
1907392

# IfcWindow: 140 x 215 cm, PF-VR-2 Vantaux:140 x 215 cm:1884591
In: Plan des fondations Maisons 1 et 2
Type - ParameterTakesPrecedence: no; Sizeable: no; Material: PVC - Blanc, Aluminium - Satiné, Béton - Ordinaire, Verre - Opaque Blanc
OverallHeight: 2.40456 m; OverallWidth: 1.5 m
Pset_QuantityTakeOff - Reference: 140 x 215 cm
Pset_WindowCommon - IsExternal: yes; Reference: 140 x 215 cm

# IfcWindow: 180 x 215 cm, PF-VR-2 Vantaux:180 x 215 cm:1884663
In: Plan des fondations Maisons 1 et 2
Type - ParameterTakesPrecedence: no; Sizeable: no; Material: PVC - Blanc, Aluminium - Satiné, Béton - Ordinaire, Verre
OverallHeight: 2.40456 m; OverallWidth: 1.9 m
Pset_QuantityTakeOff - Reference: 180 x 215 cm
Pset_WindowCommon - IsExternal: yes; Reference: 180 x 215 cm

# IfcWindow: 2.60 X 2.15 (2)
Type - OperationType: DOUBLE_PANEL_VERTICAL; ParameterTakesPrecedence: no; Sizeable: no; Material: Fenêtre - Poignée, Fenêtre - Appui, PVC Blanc, Fenêtre - Vitrage, Fenêtre - Cadre
OverallHeight: 2.265 m; OverallWidth: 2.7 m
Pset_QuantityTakeOff - Reference: 2.60 X 2.15
Pset_WindowCommon - IsExternal: yes; Reference: 2.60 X 2.15
Name (PF 2 Vantaux - Droits:2.60 X 2.15:...) | In
1884622 | Plan des fondations Maisons 1 et 2
1892924 | RDC
